! (c) 2009  Infineon Technologies AG, Munich
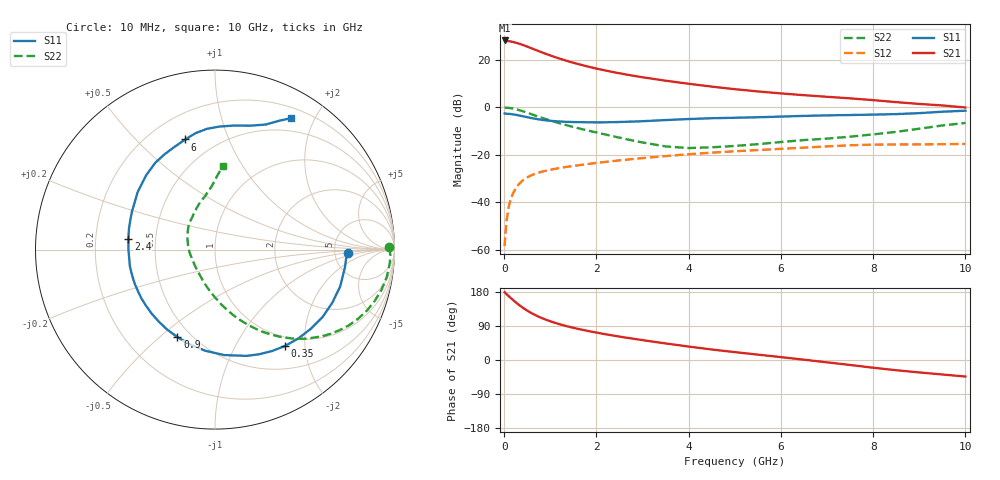
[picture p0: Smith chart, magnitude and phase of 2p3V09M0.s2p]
! Infineon Technologies  Discrete & RF Semiconductors
! BFP420
! VCE =  3.0 V,  IC =  9.0 mA
! Common Emitter S-Parameters:  Nov 2009
# GHz  S  MA  R  50
!  f  S11  S21  S12  S22
! GHz  MAG  ANG  MAG  ANG  MAG  ANG  MAG  ANG
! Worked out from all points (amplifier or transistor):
!   46 points, 10 MHz to 10 GHz, reference 50 ohm
!   highest |S21| = 28.1 dB at 10 MHz (marker M1)
!   |S21| within 3 dB of that: start of sweep to 554.8 MHz
!   unconditionally stable (mu >= 1): 2.463 GHz to end of sweep
!   at 300 MHz: K = 0.18, MSG = 29.8 dB, |S12| = -32.8 dB
!   at 1.7 GHz: K = 0.78, MSG = 20.9 dB, |S12| = -24.2 dB
!   at 10 GHz: K = 1.09, MAG = 5.8 dB, |S12| = -15.4 dB
!   S11 on the Smith chart (normalised r, x): 10 MHz: 6.61, -0.56; 350 MHz: 0.84, -1.62; 900 MHz: 0.42, -0.57; 2.4 GHz: 0.35, +0.05; 6 GHz: 0.34, +0.71; 10 GHz: 0.33, +1.68
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0.01  0.7388 -1.5  25.34 178.9  0.0012 60.1  0.9708 0.8
0.02  0.7332 -3.1  24.68 177.5  0.0017 78.9  0.9775 -1.7
0.1  0.7272 -16.4  24.45 168.4  0.0082 80.9  0.9691 -9.1
0.2  0.7076 -32.0  23.47 157.6  0.016 74.4  0.9346 -17.9
0.3  0.6785 -47.0  22.06 147.4  0.0229 68.2  0.8846 -25.9
0.35  0.6631 -54.2  21.27 142.9  0.0259 65.4  0.8561 -29.6
0.45  0.6325 -67.3  19.64 134.3  0.0313 60.4  0.7965 -36.1
0.6  0.5899 -85.0  17.25 123.2  0.0375 54.5  0.7091 -44.5
0.7  0.5664 -95.4  15.79 117.0  0.0408 51.5  0.6557 -49.1
0.9  0.5307 -113.2  13.3 106.6  0.0462 47.3  0.5649 -56.8
1  0.519 -121.1  12.27 102.2  0.0485 45.7  0.5259 -60.2
1.2  0.5017 -134.7  10.54 94.4  0.0526 43.4  0.4601 -66.1
1.4  0.4922 -146.3  9.179 87.9  0.0565 41.8  0.4075 -71.4
1.7  0.4842 -160.8  7.645 79.6  0.0619 40.0  0.3442 -78.5
2.4  0.4863 172.9  5.398 63.8  0.0746 36.3  0.2409 -95.1
3.5  0.5375 143.2  3.613 43.7  0.0939 30.1  0.1501 -132.8
4.5  0.5875 124.4  2.715 27.7  0.1109 23.1  0.1437 -175.0
5.5  0.6155 111.4  2.149 14.2  0.1259 16.1  0.1675 156.4
6  0.6357 105.1  1.954 7.6  0.1334 12.7  0.1856 144.8
7  0.6742 93.9  1.658 -6.2  0.1502 4.7  0.2191 125.9
8.5  0.7174 74.2  1.28 -27.0  0.1649 -10.8  0.3039 100.4
10  0.8454 60.0  0.988 -43.7  0.1694 -21.1  0.4672 84.7
